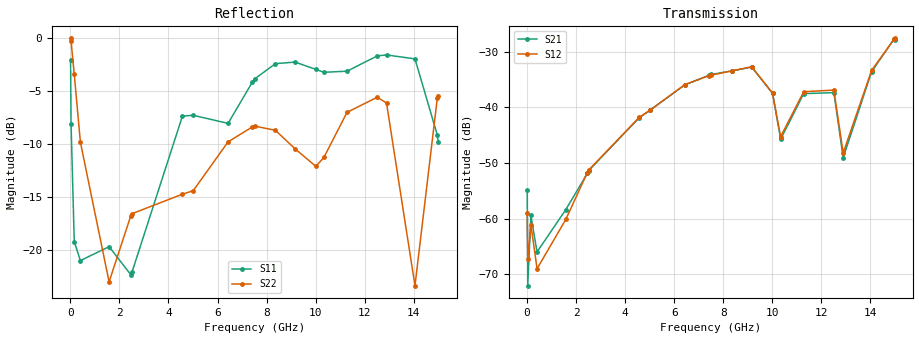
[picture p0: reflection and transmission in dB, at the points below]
!Agilent Technologies,N5230A,MY45001650,A.07.50.48
!Agilent N5230A: A.07.50.48
!Date: Wednesday, April 30, 2014 16:50:49
!Correction: S11(Full 2 Port(1,2))
!S21(Full 2 Port(1,2))
!S12(Full 2 Port(1,2))
!S22(Full 2 Port(1,2))
!S2P File: Measurements: S11, S21, S12, S22:
# Hz S  dB  R 50
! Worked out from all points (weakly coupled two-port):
!   1500 points, 10 MHz to 15 GHz, reference 50 ohm
!   highest |S21| = -27.76 dB at 14.96 GHz (marker M1); lowest = -72.1 dB at 30 MHz (marker M2)
!   lowest |S11| = -22.3 dB at 2.46 GHz (marker M3), VSWR 1.17, Z = 43.7 + j3.5 ohm
!   |S11| at or under -10 dB: 39.37 MHz to 3.833 GHz (3.793 GHz wide, 196 % of centre)
!   |S22| runs from -23.9 to 0.0 dB; largest |S21 - S12| = 0.0029
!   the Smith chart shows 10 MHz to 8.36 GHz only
!   S11 on the Smith chart (normalised r, x): 10 MHz: 1.14, -2.74; 1.58 GHz: 0.87, -0.15; 4.57 GHz: 1.57, -1.04; 6.43 GHz: 0.44, -0.08; 7.42 GHz: 0.45, +0.89; 8.36 GHz: 1.69, +2.93
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1e7  -2.06 -35.1  -54.84 -7.9  -58.94 -158.8  -0.05 -4.6
3e7  -8.14 -57.0  -72.07 -44.1  -67.35 84.3  -0.33 -13.3
1.6e8  -19.17 -51.5  -59.45 -21.9  -61.15 -1.6  -3.43 -57.8
4.1e8  -20.96 -46.7  -66.00 -21.8  -69.02 -13.5  -9.82 -101.6
1.58e9  -19.65 -125.5  -58.41 28.8  -60.17 30.1  -22.96 85.4
2.46e9  -22.27 148.8  -51.89 0.7  -51.73 0.8  -16.78 10.7
2.51e9  -22.07 142.6  -51.41 -2.1  -51.30 0.0  -16.55 8.1
4.57e9  -7.36 -39.4  -41.91 -120.5  -41.82 -120.2  -14.71 -98.3
5.01e9  -7.29 -64.5  -40.54 -145.8  -40.55 -146.1  -14.38 -132.0
6.43e9  -8.05 -168.2  -35.99 121.2  -35.92 120.9  -9.79 141.7
7.42e9  -4.17 90.1  -34.25 43.6  -34.32 43.5  -8.38 103.9
7.51e9  -3.87 83.5  -34.10 36.7  -34.23 36.5  -8.30 100.4
8.36e9  -2.43 29.3  -33.45 -29.7  -33.45 -29.4  -8.70 69.2
9.16e9  -2.28 -12.9  -32.77 -99.5  -32.71 -99.8  -10.44 33.6
1.001e10  -2.97 -63.1  -37.47 175.1  -37.47 174.9  -12.09 -30.5
1.034e10  -3.24 -87.0  -45.74 -168.5  -45.28 -166.2  -11.24 -61.7
1.128e10  -3.14 -178.7  -37.54 159.5  -37.20 159.2  -7.01 -122.5
1.251e10  -1.70 78.7  -37.37 56.8  -36.91 62.8  -5.59 -154.2
1.289e10  -1.61 59.8  -49.05 42.0  -48.19 38.2  -6.13 -159.6
1.405e10  -1.98 9.6  -33.60 -45.7  -33.35 -40.8  -23.32 -106.0
1.496e10  -9.14 -96.8  -27.76 -146.3  -27.78 -147.5  -5.67 -41.9
1.5e10  -9.84 -109.0  -27.92 -152.1  -27.61 -151.9  -5.43 -41.3
